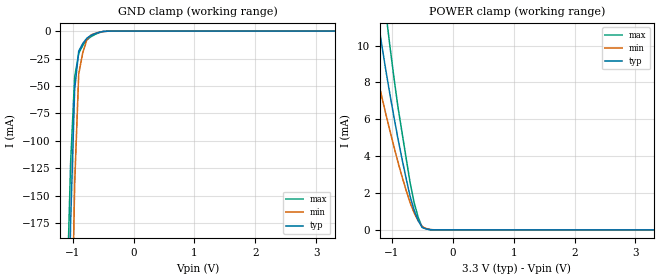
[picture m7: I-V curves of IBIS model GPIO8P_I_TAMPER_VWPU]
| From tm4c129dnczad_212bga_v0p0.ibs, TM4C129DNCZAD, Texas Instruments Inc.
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|   Model Cell GPIO8P_I_TAMPER_VWPU
[Model]   GPIO8P_I_TAMPER_VWPU
Model_type   Input
Polarity   Non-Inverting
Vinl =  0.8
Vinh =  2
C_comp   5.378567p   4.597605p   6.118031p
[Model Spec]
Vinl   0.8   0.8   0.8
Vinh   2   2   2
[Temperature Range]   25   125   -40
[Voltage Range]   3.3   2.97   3.63
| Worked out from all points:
|   GND clamp passes 1 mA (typ) near -0.55 V on its own axis
|   POWER clamp passes 1 mA (typ) near -0.63 V on its own axis
| Nom Voltages:
|   VBAT=3.3, VDDC=1.2, VDD=3.3, GND=0
| Min Voltages:
|   VBAT=2.97, VDDC=1.08, VDD=2.97, GND=0
| Max Voltages:
|   VBAT=3.63, VDDC=1.32, VDD=3.63, GND=0
[POWER_clamp]
|   voltage   I(typ)   I(min)   I(max)
-3.3V     116.2mA    496.9mA    244.4mA
-1.433V   16.05mA    11.29mA    22.45mA
-1.367V   14.49mA    10.24mA    20.21mA
-1.233V   11.5mA     8.226mA    15.9mA
-1.167V   10.08mA    7.258mA    13.86mA
-1.1V     8.696mA    6.311mA    11.87mA
-1.033V   7.401mA    5.411mA    10.03mA
-900mV    4.963mA    3.689mA    6.685mA
-700mV    1.817mA    1.472mA    2.564mA
-566.7mV  502.7uA    489.4uA    668.7uA
-500mV    124.8uA    168.6uA    137uA
3.3V      -756.4nA   -7.763uA   -1.311uA
[GND_clamp]
|   voltage   I(typ)   I(min)   I(max)
-3.3V     -16.39A    -15.37A    -17.22A
-1.1V     -384.9mA   -635.5mA   -255.1mA
-1.033V   -175.3mA   -338.1mA   -120mA
-966.7mV  -53.07mA   -139.3mA   -41.78mA
-900mV    -18.29mA   -38.89mA   -20.3mA
-833.3mV  -11.28mA   -19.6mA    -13.05mA
-766.7mV  -6.484mA   -7.834mA   -7.996mA
-700mV    -3.906mA   -3.579mA   -5.147mA
-500mV    -320.4uA   -378.8uA   -365.7uA
-366.7mV  -16.2uA    -32.29uA   -15.65uA
3.3V      361.8pA    3.703uA    -318.1nA
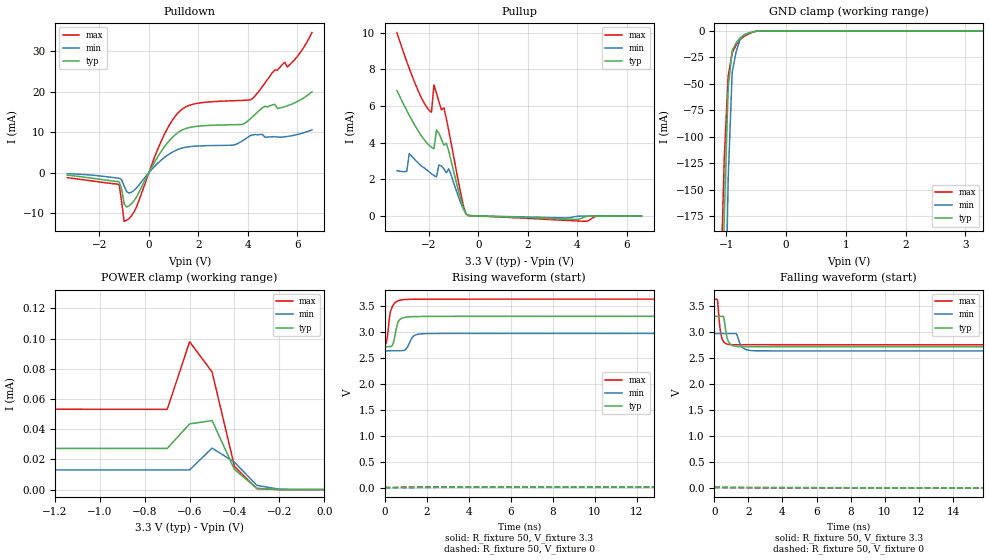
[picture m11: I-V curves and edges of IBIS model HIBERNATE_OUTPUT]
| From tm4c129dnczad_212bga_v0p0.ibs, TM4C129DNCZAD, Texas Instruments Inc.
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|   Model Cell HIBERNATE_OUTPUT
[Model]   HIBERNATE_OUTPUT
Model_type   Output
Polarity   Non-Inverting
Enable   Active-Low
Cref =  15.0000pF
Rref =  100.0000M
Vref =  0V
Vmeas =  1.65
C_comp   5.465001p   4.617803p   6.275566p
[Model Spec]
Vinl   0.8   0.8   0.8
Vinh   2   2   2
[Temperature Range]   25   125   -40
[Voltage Range]   3.3   2.97   3.63
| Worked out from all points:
|   slope of the pulldown table from 0 to 0.495 V, typ, clamps not added: 95.1 ohm
|   slope of the pullup table from 0 to 0.495 V, typ, clamps not added: 21.1 kohm
|   GND clamp passes 1 mA (typ) near -0.55 V on its own axis
|   rising waveform, R_fixture 50, V_fixture 3.3: 20-80 % time 190ps typ, 262ps min, 196ps max; typ from 2.71 V to 3.3 V
|   falling waveform, R_fixture 50, V_fixture 3.3: 20-80 % time 210ps typ, 280ps min, 175ps max; typ from 3.3 V to 2.71 V
| Nom Voltages:
|   IBIASFET=3.3, VDDC=1.2, VDD=3.3, GND=0
| Min Voltages:
|   IBIASFET=2.97, VDDC=1.08, VDD=2.97, GND=0
| Max Voltages:
|   IBIASFET=3.63, VDDC=1.32, VDD=3.63, GND=0
[POWER_clamp]
|   voltage   I(typ)   I(min)   I(max)
-3.3V     115.1uA    433.3mA    64.95uA
-3.2V     32.43uA    390.6mA    63.45uA
-3V       29.84uA    305.6mA    60.86uA
-2.033V   27.65uA    244.4uA    54.35uA
-2V       27.61uA    48.33uA    54.25uA
-1.9V     27.53uA    15.07uA    54uA
-700mV    27.24uA    13.03uA    53.12uA
-600mV    43.52uA    13.03uA    97.89uA
-500mV    45.71uA    27.48uA    77.88uA
-400mV    13.32uA    18.12uA    15.3uA
-300mV    859.4nA    2.798uA    598.6nA
0V        395.6pA    9.845nA    58.24pA
[Pulldown]
|   voltage   I(typ)   I(min)   I(max)
-3.3V     -584.3uA   -253.2uA   -1.21mA
-1.2V     -2.217mA   -1.357mA   -2.926mA
-1V       -7.684mA   -3.316mA   -11.96mA
-900mV    -8.44mA    -4.658mA   -11.73mA
-500mV    -5.974mA   -3.755mA   -8.425mA
600mV     6.131mA    3.613mA    9.08mA
1.2V      9.981mA    5.78mA     14.86mA
3.4V      11.82mA    6.782mA    17.72mA
4.2V      13.78mA    9.306mA    18.29mA
5.1V      16.84mA    8.882mA    25.31mA
5.9V      17.2mA     9.265mA    27.85mA
6.6V      19.92mA    10.55mA    34.51mA
[Pullup]
|   voltage   I(typ)   I(min)   I(max)
-3.3V     6.85mA     2.467mA    10.02mA
-2.9V     5.76mA     2.434mA    8.432mA
-2.8V     5.502mA    3.414mA    8.06mA
-2.1V     4.009mA    2.529mA    5.955mA
-1.9V     3.751mA    2.302mA    5.667mA
-1.8V     3.667mA    2.207mA    7.157mA
-1.7V     4.691mA    2.125mA    6.712mA
-1.6V     4.518mA    2.782mA    6.249mA
-1.4V     3.865mA    2.576mA    5.901mA
-1.2V     3.533mA    2.573mA    4.642mA
-500mV    92.09uA    108.5uA    109.3uA
6.6V      -5.965uA   -3.806uA   -4.258uA
[GND_clamp]
|   voltage   I(typ)   I(min)   I(max)
-3.3V     -16.39A    -15.37A    -17.22A
-1.1V     -385.1mA   -635.6mA   -256.3mA
-1.033V   -175.6mA   -338.3mA   -121.2mA
-966.7mV  -53.38mA   -139.4mA   -42.75mA
-900mV    -18.52mA   -39.05mA   -20.75mA
-833.3mV  -11.44mA   -19.73mA   -13.31mA
-766.7mV  -6.599mA   -7.926mA   -8.148mA
-700mV    -3.986mA   -3.644mA   -5.249mA
-500mV    -328.3uA   -388.2uA   -374.5uA
-366.7mV  -15.94uA   -32.84uA   -14.83uA
3.3V      395.6pA    5.294uA    29.38pA
[Ramp]
| variable   typ   min   max
dV/dt_f 0.35218876/0.20991049n 0.20152292/0.2803063n 0.52770882/0.17505111n
dV/dt_r 8.4224118m/1.0564892n 5.5987287m/1.6135034n 11.169512m/0.67867353n
R_load = 50
[Rising Waveform]
R_fixture = 50
V_fixture = 3.3
V_fixture_min = 2.97
V_fixture_max = 3.63
|   time   V(typ)   V(min)   V(max)
0s        2.714V     2.635V     2.752V
102.4ps   2.714V     2.635V     2.837V
271.9ps   2.714V     2.635V     3.381V
427.2ps   2.806V     2.635V     3.528V
612.4ps   3.16V      2.635V     3.595V
993.3ps   3.28V      2.661V     3.624V
1.313ns   3.292V     2.891V     3.627V
1.526ns   3.295V     2.949V     3.628V
3.933ns   3.299V     2.969V     3.63V
5us       3.3V       2.97V      3.63V
[Rising Waveform]
R_fixture = 50
V_fixture = 0
V_fixture_min = 0
V_fixture_max = 0
|   time   V(typ)   V(min)   V(max)
0s        0V         0V         0V
317.5ps   0V         0V         0V
347.8ps   -4.094mV   0V         2.439mV
539ps     -6.016mV   0V         0V
782.3ps   2.829mV    0V         10.88mV
1.078ns   0V         -4.189mV   12.5mV
1.539ns   6.139mV    0V         12.4mV
3.028ns   7.561mV    3.65mV     12.37mV
22.27ns   7.983mV    4.583mV    12.37mV
5us       7.983mV    4.585mV    12.37mV
[Falling Waveform]
R_fixture = 50
V_fixture = 3.3
V_fixture_min = 2.97
V_fixture_max = 3.63
|   time   V(typ)   V(min)   V(max)
0s        3.3V       2.97V      3.63V
186.2ps   3.301V     2.97V      3.616V
375.2ps   3.301V     2.97V      2.981V
543.8ps   3.293V     2.97V      2.813V
705.9ps   2.957V     2.971V     2.771V
1.051ns   2.742V     2.97V      2.756V
1.637ns   2.717V     2.708V     2.755V
2.072ns   2.716V     2.645V     2.755V
7.562ns   2.715V     2.636V     2.753V
5us       2.714V     2.635V     2.752V
[Falling Waveform]
R_fixture = 50
V_fixture = 0
V_fixture_min = 0
V_fixture_max = 0
|   time   V(typ)   V(min)   V(max)
0s        7.983mV    4.585mV    12.37mV
393.4ps   8.898mV    4.589mV    9.207mV
527.8ps   16.23mV    4.538mV    6.901mV
819.6ps   6.929mV    5.618mV    6.261mV
1.083ns   4.951mV    5.475mV    6.146mV
1.267ns   4.793mV    10.49mV    5.991mV
2.075ns   4.663mV    3.345mV    5.207mV
7.228ns   2.648mV    2.606mV    0V
10.53ns   0V         2.143mV    0V
5us       0V         0V         0V
